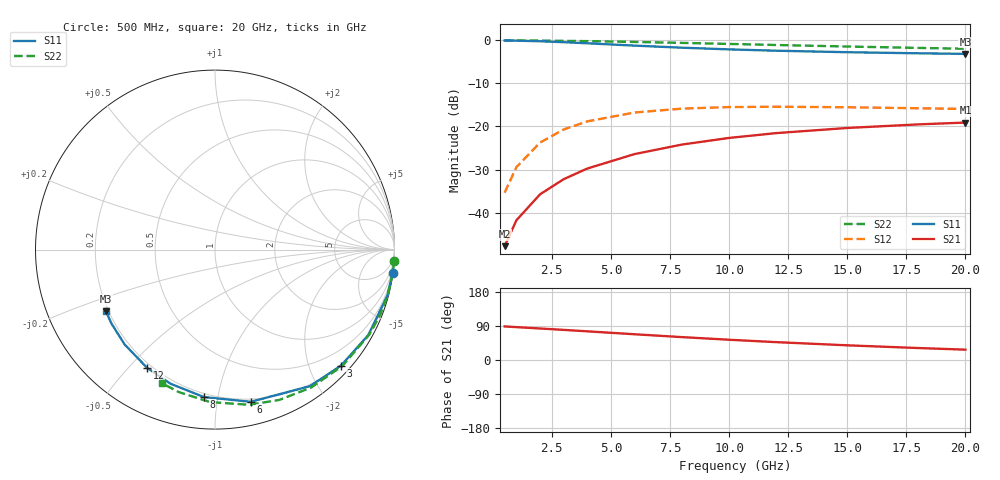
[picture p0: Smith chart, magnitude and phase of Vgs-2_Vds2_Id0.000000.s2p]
# Hz S RI R 50
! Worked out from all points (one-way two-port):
!   12 points, 500 MHz to 20 GHz, reference 50 ohm
!   highest |S21| = -19.09 dB at 20 GHz (marker M1); lowest = -47.8 dB at 500 MHz (marker M2)
!   lowest |S11| = -3.1 dB at 20 GHz (marker M3), VSWR 5.62, Z = 9.49 - j12.7 ohm
!   |S11| at or under -10 dB: nowhere
!   |S22| runs from -1.9 to 0.0 dB; largest |S21 - S12| = 0.12
!   S11 on the Smith chart (normalised r, x): 500 MHz: 0, -15; 3 GHz: 0.18, -2.55; 6 GHz: 0.18, -1.25; 8 GHz: 0.18, -0.91; 12 GHz: 0.18, -0.56; 20 GHz: 0.19, -0.25
5e8  0.9902 -0.1289  9.86e-05 0.00407  0.00162 0.0169  0.9976 -0.064
1e9  0.9613 -0.2536  0.000463 0.00812  0.00638 0.0331  0.9906 -0.1275
2e9  0.8544 -0.4759  0.00195 0.0162  0.0238 0.0606  0.963 -0.2511
3e9  0.702 -0.6464  0.00447 0.024  0.048 0.0789  0.9186 -0.3674
4e9  0.5296 -0.7605  0.00805 0.0315  0.0743 0.0874  0.8595 -0.4739
6e9  0.1991 -0.848  0.018 0.0443  0.1201 0.0819  0.7095 -0.6484
8e9  -0.0614 -0.8215  0.0305 0.0536  0.1494 0.0609  0.5355 -0.7686
1e10  -0.248 -0.7472  0.0439 0.0592  0.164 0.0371  0.3584 -0.8375
1.2e10  -0.378 -0.6589  0.0571 0.0614  0.169 0.0158  0.1911 -0.8645
1.5e10  -0.5031 -0.5288  0.075 0.0602  0.1671 -0.00885  -0.0274 -0.8495
1.8e10  -0.5765 -0.4128  0.0901 0.0554  0.1609 -0.0258  -0.2021 -0.7937
2e10  -0.6075 -0.3438  0.0987 0.051  0.1562 -0.0341  -0.2962 -0.7441
